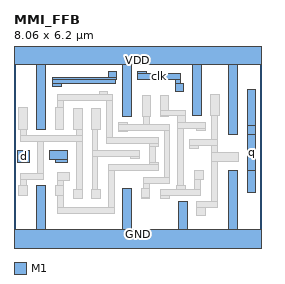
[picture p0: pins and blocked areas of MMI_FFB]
MACRO MMI_FFB
	CLASS CORE ;
	FOREIGN MMI_FFB 0 0 ;
	SIZE 8.06 BY 6.2 ;
	SYMMETRY X Y ;
	SITE CORE1 ;
	PIN d
		DIRECTION input ;
		USE SIGNAL ;
		PORT
			LAYER M1 ;
			RECT 0.12 2.585 0.5 2.985 ;
		END
		AntennaGateArea 0.17325 ;
	END d
	PIN GND
		DIRECTION inout ;
		USE GROUND ;
		PORT
			LAYER M1 ;
			RECT 0.75 0.42 1.03 1.84 ;
			LAYER M1 ;
			RECT 3.555 0.42 3.835 1.745 ;
			LAYER M1 ;
			RECT 5.38 0.42 5.66 1.32 ;
			LAYER M1 ;
			RECT 7.015 0.42 7.295 2.32 ;
			LAYER M1 ;
			RECT 0 -0.42 8.06 0.42 ;
		END
	END GND
	PIN q
		DIRECTION output ;
		USE SIGNAL ;
		PORT
			LAYER M1 ;
			RECT 7.605 3.79 7.885 4.98 ;
			LAYER M1 ;
			RECT 7.605 3.51 7.895 3.79 ;
			LAYER M1 ;
			RECT 7.61 2.32 7.895 3.51 ;
			LAYER M1 ;
			RECT 7.605 1.63 7.895 2.32 ;
			LAYER M1 ;
			RECT 7.605 1.62 7.885 1.63 ;
		END
		AntennaDiffArea 0.91245 ;
	END q
	PIN VDD
		DIRECTION inout ;
		USE POWER ;
		PORT
			LAYER M1 ;
			RECT 0 5.78 8.06 6.62 ;
			LAYER M1 ;
			RECT 0.75 3.685 1.03 5.78 ;
			LAYER M1 ;
			RECT 3.55 4.09 3.83 5.78 ;
			LAYER M1 ;
			RECT 5.825 4.115 6.105 5.78 ;
			LAYER M1 ;
			RECT 7.015 3.51 7.295 5.78 ;
		END
	END VDD
	PIN clk
		DIRECTION input ;
		USE CLOCK ;
		PORT
			LAYER M1 ;
			RECT 3.07 5.365 3.35 5.58 ;
			LAYER M1 ;
			RECT 1.34 5.36 3.35 5.365 ;
			LAYER M1 ;
			RECT 1.27 5.3 3.35 5.36 ;
			LAYER M1 ;
			RECT 4.03 5.5 4.31 5.58 ;
			LAYER M1 ;
			RECT 4.03 5.31 5.445 5.5 ;
			LAYER M1 ;
			RECT 4.03 5.3 4.31 5.31 ;
			LAYER M1 ;
			RECT 1.27 5.17 3.31 5.3 ;
			LAYER M1 ;
			RECT 5.255 5.185 5.445 5.31 ;
			LAYER M1 ;
			RECT 1.27 5.08 1.55 5.17 ;
			LAYER M1 ;
			RECT 5.255 4.905 5.535 5.185 ;
			LAYER M1 ;
			RECT 1.365 2.975 1.745 2.98 ;
			LAYER M1 ;
			RECT 1.16 2.695 1.745 2.975 ;
			LAYER M1 ;
			RECT 1.365 2.6 1.745 2.695 ;
		END
		AntennaGateArea 0.44625 ;
	END clk
	OBS
		LAYER M1 ;
		RECT 0.16 3.685 0.44 4.385 ;
		LAYER M1 ;
		RECT 2.785 4.805 3.065 4.92 ;
		LAYER M1 ;
		RECT 1.43 4.615 3.215 4.805 ;
		LAYER M1 ;
		RECT 1.43 4.385 1.62 4.615 ;
		LAYER M1 ;
		RECT 1.34 3.685 1.62 4.385 ;
		LAYER M1 ;
		RECT 0.2 3.47 0.395 3.685 ;
		LAYER M1 ;
		RECT 1.955 3.67 2.235 4.37 ;
		LAYER M1 ;
		RECT 2.545 3.67 2.825 4.37 ;
		LAYER M1 ;
		RECT 2.03 3.47 2.225 3.67 ;
		LAYER M1 ;
		RECT 0.2 3.275 2.225 3.47 ;
		LAYER M1 ;
		RECT 0.765 2.23 0.955 3.275 ;
		LAYER M1 ;
		RECT 0.21 2.04 0.955 2.23 ;
		LAYER M1 ;
		RECT 0.21 1.84 0.4 2.04 ;
		LAYER M1 ;
		RECT 1.435 1.995 1.815 2.275 ;
		LAYER M1 ;
		RECT 1.435 1.84 1.625 1.995 ;
		LAYER M1 ;
		RECT 0.16 1.525 0.44 1.84 ;
		LAYER M1 ;
		RECT 1.34 1.525 1.625 1.84 ;
		LAYER M1 ;
		RECT 2.03 1.71 2.225 3.275 ;
		LAYER M1 ;
		RECT 2.55 2.995 2.74 3.67 ;
		LAYER M1 ;
		RECT 3.025 3.4 3.215 4.615 ;
		LAYER M1 ;
		RECT 4.185 4.09 4.465 4.79 ;
		LAYER M1 ;
		RECT 4.775 4.305 5.055 4.79 ;
		LAYER M1 ;
		RECT 4.775 4.115 5.6 4.305 ;
		LAYER M1 ;
		RECT 6.415 4.115 6.695 4.815 ;
		LAYER M1 ;
		RECT 4.775 4.09 5.055 4.115 ;
		LAYER M1 ;
		RECT 3.415 3.83 3.695 3.89 ;
		LAYER M1 ;
		RECT 4.22 3.83 4.415 4.09 ;
		LAYER M1 ;
		RECT 5.34 3.91 5.6 4.115 ;
		LAYER M1 ;
		RECT 3.415 3.635 5.09 3.83 ;
		LAYER M1 ;
		RECT 3.415 3.61 3.695 3.635 ;
		LAYER M1 ;
		RECT 3.025 3.205 4.7 3.4 ;
		LAYER M1 ;
		RECT 4.42 3.12 4.7 3.205 ;
		LAYER M1 ;
		RECT 2.55 2.8 4.085 2.995 ;
		LAYER M1 ;
		RECT 2.55 1.71 2.74 2.8 ;
		LAYER M1 ;
		RECT 3.805 2.715 4.085 2.8 ;
		LAYER M1 ;
		RECT 4.43 2.605 4.62 3.12 ;
		LAYER M1 ;
		RECT 4.42 2.515 4.7 2.605 ;
		LAYER M1 ;
		RECT 3.085 2.325 4.7 2.515 ;
		LAYER M1 ;
		RECT 1.435 1.12 1.625 1.525 ;
		LAYER M1 ;
		RECT 1.955 1.43 2.235 1.71 ;
		LAYER M1 ;
		RECT 2.545 1.43 2.825 1.71 ;
		LAYER M1 ;
		RECT 3.085 1.12 3.275 2.325 ;
		LAYER M1 ;
		RECT 4.9 2.105 5.09 3.635 ;
		LAYER M1 ;
		RECT 4.24 1.91 5.09 2.105 ;
		LAYER M1 ;
		RECT 5.34 3.72 6.245 3.91 ;
		LAYER M1 ;
		RECT 4.24 1.745 4.435 1.91 ;
		LAYER M1 ;
		RECT 5.34 1.84 5.535 3.72 ;
		LAYER M1 ;
		RECT 5.965 3.63 6.245 3.72 ;
		LAYER M1 ;
		RECT 6.445 3.34 6.635 4.115 ;
		LAYER M1 ;
		RECT 5.82 3.335 6.635 3.34 ;
		LAYER M1 ;
		RECT 5.735 3.145 6.635 3.335 ;
		LAYER M1 ;
		RECT 5.735 3.055 6.015 3.145 ;
		LAYER M1 ;
		RECT 6.445 2.91 6.635 3.145 ;
		LAYER M1 ;
		RECT 6.445 2.63 7.34 2.91 ;
		LAYER M1 ;
		RECT 6.445 2.625 6.97 2.63 ;
		LAYER M1 ;
		RECT 5.89 2.04 6.17 2.32 ;
		LAYER M1 ;
		RECT 1.435 0.93 3.275 1.12 ;
		LAYER M1 ;
		RECT 4.145 1.455 4.435 1.745 ;
		LAYER M1 ;
		RECT 5.305 1.71 5.585 1.84 ;
		LAYER M1 ;
		RECT 5.89 1.71 6.085 2.04 ;
		LAYER M1 ;
		RECT 4.78 1.52 6.085 1.71 ;
		LAYER M1 ;
		RECT 4.145 1.43 4.425 1.455 ;
		LAYER M1 ;
		RECT 4.78 1.43 5.06 1.52 ;
		LAYER M1 ;
		RECT 6.445 1.32 6.635 2.625 ;
		LAYER M1 ;
		RECT 5.97 1.13 6.635 1.32 ;
		LAYER M1 ;
		RECT 5.97 0.87 6.25 1.13 ;
	END
END MMI_FFB
